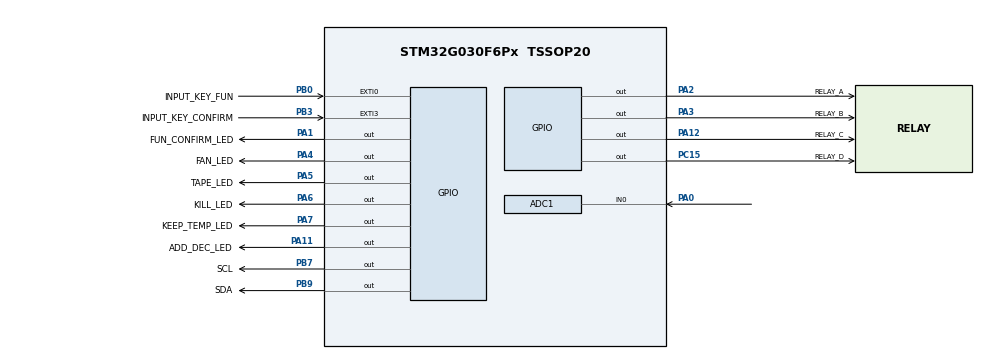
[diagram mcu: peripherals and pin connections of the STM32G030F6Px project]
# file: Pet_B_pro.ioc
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ADC1.Channel-0\#ChannelRegularConversion=ADC_CHANNEL_0
ADC1.NbrOfConversionFlag=1
ADC1.Rank-0\#ChannelRegularConversion=1
ADC1.SamplingTime-0\#ChannelRegularConversion=ADC_SAMPLINGTIME_COMMON_1
ADC1.SelectedChannel=ADC_CHANNEL_0
ADC1.master=1
FREERTOS.Tasks01=defaultTask,0,128,StartDefaultTask,Default,NULL,Dynamic,NULL,NULL
Mcu.Family=STM32G0
Mcu.Name=STM32G030F6Px
Mcu.Package=TSSOP20
NVIC.EXTI0_1_IRQn=true\:3\:0\:false\:false\:true\:true\:true\:true\:true
NVIC.EXTI2_3_IRQn=true\:0\:0\:false\:false\:true\:false\:true\:true\:true
NVIC.TIM14_IRQn=true\:3\:0\:false\:false\:true\:true\:true\:true\:true
PA0.Mode=IN0
PA0.Signal=ADC1_IN0
PA1.GPIO_Label=FUN_CONFIRM_LED
PA1.Signal=GPIO_Output
PA11\ [PA9].GPIO_Label=ADD_DEC_LED
PA11\ [PA9].Signal=GPIO_Output
PA12\ [PA10].GPIO_Label=RELAY_C
PA12\ [PA10].Signal=GPIO_Output
PA13.Mode=Serial_Wire
PA13.Signal=SYS_SWDIO
PA14-BOOT0.Mode=Serial_Wire
PA14-BOOT0.Signal=SYS_SWCLK
PA14-BOOT0__PA15.StandardMode=true
PA2.GPIO_Label=RELAY_A
PA2.Signal=GPIO_Output
PA3.GPIO_Label=RELAY_B
PA3.Signal=GPIO_Output
PA4.GPIO_Label=FAN_LED
PA4.Signal=GPIO_Output
PA5.GPIO_Label=TAPE_LED
PA5.Signal=GPIO_Output
PA6.GPIO_Label=KILL_LED
PA6.Signal=GPIO_Output
PA7.GPIO_Label=KEEP_TEMP_LED
PA7.Signal=GPIO_Output
PB0.GPIO_Label=INPUT_KEY_FUN
PB0.Signal=GPXTI0
PB0__PB1__PB2__PA8.StandardMode=true
PB3.GPIO_Label=INPUT_KEY_CONFIRM
PB3.GPIO_ModeDefaultEXTI=GPIO_MODE_IT_FALLING
PB3.GPIO_PuPd=GPIO_PULLUP
PB3.Signal=GPXTI3
PB3__PB4__PB5__PB6.StandardMode=true
PB7.GPIO_Label=SCL
PB7.Signal=GPIO_Output
PB7__PB8.StandardMode=true
PB9.GPIO_Label=SDA
PB9.Signal=GPIO_Output
PC14-OSC32_IN\ (PC14)__PB9.StandardMode=true
PC15-OSC32_OUT\ (PC15).GPIO_Label=RELAY_D
PC15-OSC32_OUT\ (PC15).Signal=GPIO_Output
ProjectManager.HeapSize=0x200
ProjectManager.StackSize=0x400
ProjectManager.TargetToolchain=MDK-ARM V5.32
RCC.ADCFreq_Value=24000000
RCC.AHBFreq_Value=24000000
RCC.CortexFreq_Value=24000000
RCC.EXTERNAL_CLOCK_VALUE=12288000
RCC.HCLKFreq_Value=24000000
RCC.HSE_VALUE=8000000
RCC.HSI_VALUE=16000000
RCC.LSE_VALUE=32768
RCC.PLLN=9
RCC.PLLR=RCC_PLLR_DIV6
RCC.SYSCLKFreq_VALUE=24000000
RCC.SYSCLKSource=RCC_SYSCLKSOURCE_PLLCLK
RCC.VCOOutputFreq_Value=144000000
VP_FREERTOS_VS_CMSIS_V1.Mode=CMSIS_V1
VP_IWDG_VS_IWDG.Mode=IWDG_Activate
VP_TIM14_VS_ClockSourceINT.Mode=Enable_Timer
board=custom

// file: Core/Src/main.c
/* USER CODE BEGIN Header */
/**
  ******************************************************************************
  * @file           : main.c
  * @brief          : Main program body
  ******************************************************************************
  * @attention
  *
  * Pet-B Version : 2.0  DATA:2024.01.13
  * Pet-B Version : 2.1  DATA:2024.01.23  modify touchkey
  * Pet-B Version : 2.2  DATA:2024.03.23  modify touchkey ->pet_b office
  * Pet-B Version : 2.3  DATA:2024.05.17  modify touchkey
  *        modify read net temperature value is linera.
  * Pet-B Version : 2.6  DATA:2024.09.12
  *
  *
  *
  *
  ******************************************************************************
  */
/* USER CODE END Header */
#include "main.h"
#include "cmsis_os.h"
#include "adc.h"
#include "iwdg.h"
#include "tim.h"
#include "gpio.h"

/* USER CODE BEGIN Includes */
#include "bsp.h"
/* USER CODE END Includes */

/* USER CODE BEGIN PTD */

uint8_t key_value;
/* USER CODE END PTD */

void SystemClock_Config(void);
void MX_FREERTOS_Init(void);

int main(void)
{

  /* MCU Configuration--------------------------------------------------------*/

  /* Reset of all peripherals, Initializes the Flash interface and the Systick. */
   HAL_Init();

  /* Configure the system clock */
  SystemClock_Config();

  /* Initialize all configured peripherals */
  MX_GPIO_Init();
  MX_ADC1_Init();
  MX_IWDG_Init();
  MX_TIM14_Init();
  /* USER CODE BEGIN 2 */
   bsp_ctl_init();
   delay_init(64);
   Relay_Init();
   HAL_TIM_Base_Start_IT(&htim14);//HAL_TIM_Base_Start(&htim3);

   freeRTOS_Handler();

  /* USER CODE END 2 */

  /* Call init function for freertos objects (in cmsis_os2.c) */
 // MX_FREERTOS_Init();

  /* Start scheduler */
 // osKernelStart();

  /* We should never get here as control is now taken by the scheduler */

  /* Infinite loop */
  while (1)
  {

    }
}

void SystemClock_Config(void)
{
  RCC_OscInitTypeDef RCC_OscInitStruct = {0};
  RCC_ClkInitTypeDef RCC_ClkInitStruct = {0};

  /** Configure the main internal regulator output voltage
  */
  HAL_PWREx_ControlVoltageScaling(PWR_REGULATOR_VOLTAGE_SCALE1);

  /** Initializes the RCC Oscillators according to the specified parameters
  * in the RCC_OscInitTypeDef structure.
  */
  RCC_OscInitStruct.OscillatorType = RCC_OSCILLATORTYPE_HSI;
  RCC_OscInitStruct.HSIState = RCC_HSI_ON;
  RCC_OscInitStruct.HSIDiv = RCC_HSI_DIV1;
  RCC_OscInitStruct.HSICalibrationValue = RCC_HSICALIBRATION_DEFAULT;
  RCC_OscInitStruct.PLL.PLLState = RCC_PLL_ON;
  RCC_OscInitStruct.PLL.PLLSource = RCC_PLLSOURCE_HSI;
  RCC_OscInitStruct.PLL.PLLM = RCC_PLLM_DIV1;
  RCC_OscInitStruct.PLL.PLLN = 8;
  RCC_OscInitStruct.PLL.PLLP = RCC_PLLP_DIV2;
  RCC_OscInitStruct.PLL.PLLR = RCC_PLLR_DIV2;
  if (HAL_RCC_OscConfig(&RCC_OscInitStruct) != HAL_OK)
  {
    Error_Handler();
  }

  /** Initializes the CPU, AHB and APB buses clocks
  */
  RCC_ClkInitStruct.ClockType = RCC_CLOCKTYPE_HCLK|RCC_CLOCKTYPE_SYSCLK
                              |RCC_CLOCKTYPE_PCLK1;
  RCC_ClkInitStruct.SYSCLKSource = RCC_SYSCLKSOURCE_PLLCLK;
  RCC_ClkInitStruct.AHBCLKDivider = RCC_SYSCLK_DIV1;
  RCC_ClkInitStruct.APB1CLKDivider = RCC_HCLK_DIV1;

  if (HAL_RCC_ClockConfig(&RCC_ClkInitStruct, FLASH_LATENCY_2) != HAL_OK)
  {
    Error_Handler();
  }
}

void Error_Handler(void)
{
  __disable_irq();
  while (1)
  {
  }
}
